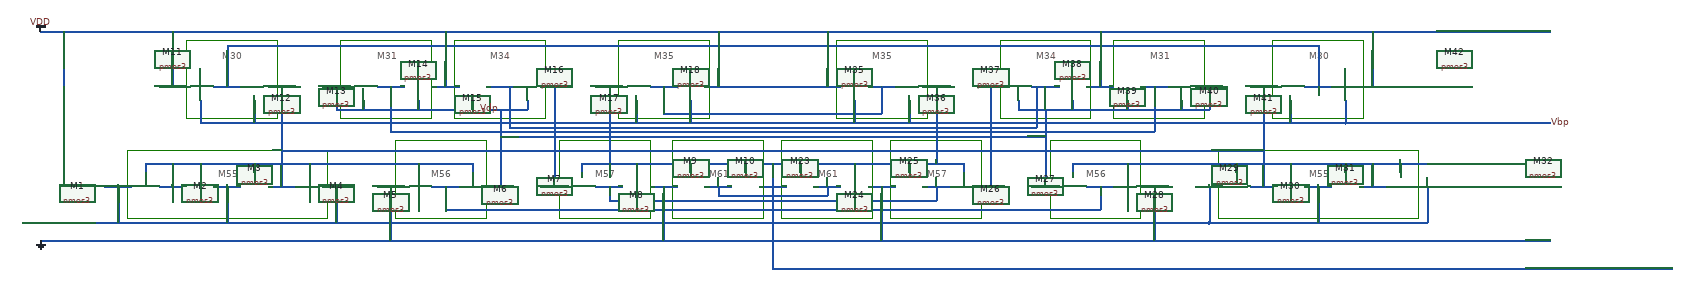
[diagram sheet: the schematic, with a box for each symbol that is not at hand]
v {xschem version=2.9.9 file_version=1.2 }
G {}
K {}
V {}
S {}
E {}
L 4 -700 -60 -500 -60 {}
L 4 -500 -230 -500 -60 {}
L 4 -700 -230 -500 -230 {}
L 4 -700 -230 -700 -60 {}
L 4 500 -60 700 -60 {}
L 4 700 -230 700 -60 {}
L 4 500 -230 700 -230 {}
L 4 500 -230 500 -60 {}
L 4 750 -60 950 -60 {}
L 4 950 -230 950 -60 {}
L 4 750 -230 950 -230 {}
L 4 750 -230 750 -60 {}
L 4 -950 -60 -750 -60 {}
L 4 -750 -230 -750 -60 {}
L 4 -950 -230 -750 -230 {}
L 4 -950 -230 -950 -60 {}
L 4 -1290 -60 -1090 -60 {}
L 4 -1090 -230 -1090 -60 {}
L 4 -1290 -230 -1090 -230 {}
L 4 -1290 -230 -1290 -60 {}
L 4 140 -60 340 -60 {}
L 4 340 -230 340 -60 {}
L 4 140 -230 340 -230 {}
L 4 140 -230 140 -60 {}
L 4 20 160 220 160 {}
L 4 220 -10 220 160 {}
L 4 20 -10 220 -10 {}
L 4 20 -10 20 160 {}
L 4 -220 160 -20 160 {}
L 4 -20 -10 -20 160 {}
L 4 -220 -10 -20 -10 {}
L 4 -220 -10 -220 160 {}
L 4 -470 160 -270 160 {}
L 4 -270 -10 -270 160 {}
L 4 -470 -10 -270 -10 {}
L 4 -470 -10 -470 160 {}
L 4 1100 -60 1300 -60 {}
L 4 1300 -230 1300 -60 {}
L 4 1100 -230 1300 -230 {}
L 4 1100 -230 1100 -60 {}
L 4 -1420 10 -1420 160 {}
L 4 -1420 160 -980 160 {}
L 4 -980 10 -980 160 {}
L 4 -1420 10 -980 10 {}
L 4 980 10 980 160 {}
L 4 980 160 1420 160 {}
L 4 1420 10 1420 160 {}
L 4 980 10 1420 10 {}
L 4 -830 160 -630 160 {}
L 4 -630 -10 -630 160 {}
L 4 -830 -10 -630 -10 {}
L 4 -830 -10 -830 160 {}
L 4 610 160 810 160 {}
L 4 810 -10 810 160 {}
L 4 610 -10 810 -10 {}
L 4 610 -10 610 160 {}
L 4 -340 -60 -140 -60 {}
L 4 -140 -230 -140 -60 {}
L 4 -340 -230 -140 -230 {}
L 4 -340 -230 -340 -60 {}
L 4 260 160 460 160 {}
L 4 460 -10 460 160 {}
L 4 260 -10 460 -10 {}
L 4 260 -10 260 160 {}
T {M34} -620 -210 0 0 0.4 0.4 {}
T {M34} 580 -210 0 0 0.4 0.4 {}
T {M31} 830 -210 0 0 0.4 0.4 {}
T {M31} -870 -210 0 0 0.4 0.4 {}
T {M30} -1210 -210 0 0 0.4 0.4 {}
T {M35} 220 -210 0 0 0.4 0.4 {}
T {M30} 1180 -210 0 0 0.4 0.4 {}
T {M55} -1220 50 0 0 0.4 0.4 {}
T {M55} 1180 50 0 0 0.4 0.4 {}
T {M56} -750 50 0 0 0.4 0.4 {}
T {M56} 690 50 0 0 0.4 0.4 {}
T {M35} -260 -210 0 0 0.4 0.4 {}
T {M57} 340 50 0 0 0.4 0.4 {}
T {M57} -390 50 0 0 0.4 0.4 {}
T {M61} -140 50 0 0 0.4 0.4 {}
T {M61} 100 50 0 0 0.4 0.4 {}
N -1020 40 -1020 60 { lab=#net1}
N -1140 40 -1140 60 { lab=#net1}
N -1260 40 -1260 60 { lab=#net1}
N -1380 40 -1380 60 { lab=#net1}
N -1350 90 -1290 90 { lab=#net1}
N -1230 90 -1170 90 { lab=#net2}
N -1110 90 -1050 90 { lab=#net1}
N -1230 -130 -1170 -130 { lab=#net3}
N -870 -130 -810 -130 { lab=#net4}
N -630 -130 -570 -130 { lab=#net5}
N -270 -130 -210 -130 { lab=#net6}
N -900 -100 -900 -80 { lab=Vdp}
N -540 -100 -540 -80 { lab=Vdp}
N -780 -100 -780 -80 { lab=Vdp}
N -660 -100 -660 -80 { lab=Vdp}
N -1260 -100 -1260 -50 { lab=Vbp}
N -180 -100 -180 -50 { lab=Vbp}
N -300 -100 -300 -50 { lab=Vbp}
N -1140 -100 -1140 -50 { lab=Vbp}
N -1320 -250 -1320 -130 { lab=VDD}
N -120 -250 -120 -130 { lab=VDD}
N -750 -130 -690 -130 { lab=VDD}
N -720 -250 -720 -130 { lab=VDD}
N -780 40 -780 60 { lab=#net1}
N -660 40 -660 60 { lab=#net1}
N -750 90 -690 90 { lab=#net7}
N -390 90 -330 90 { lab=#net8}
N -150 90 -90 90 { lab=#net9}
N -960 90 -960 170 { lab=#net2}
N -420 40 -420 60 { lab=#net10}
N -60 40 -60 60 { lab=#net10}
N -180 40 -180 60 { lab=#net10}
N -300 40 -300 60 { lab=#net10}
N -270 90 -210 90 { lab=GND}
N -240 90 -240 210 { lab=GND}
N -840 90 -840 210 { lab=GND}
N 0 40 0 90 { lab=#net10}
N -480 -50 -480 90 { lab=Vbp}
N -1110 -130 -1050 -130 { lab=#net1}
N -990 -130 -930 -130 { lab=Vdp}
N -1080 -130 -1080 40 { lab=#net1}
N -390 -130 -330 -130 { lab=#net10}
N -360 -130 -360 40 { lab=#net10}
N -510 -130 -450 -130 { lab=Vbp}
N -480 -130 -480 -50 { lab=Vbp}
N -870 90 -810 90 { lab=GND}
N -990 90 -930 90 { lab=#net2}
N -630 90 -570 90 { lab=Vdp}
N -600 -80 -600 90 { lab=Vdp}
N -510 90 -450 90 { lab=Vbp}
N 60 40 60 60 { lab=#net10}
N 180 40 180 60 { lab=#net10}
N 300 40 300 60 { lab=#net10}
N 420 40 420 60 { lab=#net10}
N -30 90 30 90 { lab=#net10}
N -420 40 420 40 { lab=#net10}
N 90 90 150 90 { lab=#net9}
N 210 90 270 90 { lab=GND}
N 330 90 390 90 { lab=#net8}
N 240 90 240 210 { lab=GND}
N -150 -130 -90 -130 { lab=VDD}
N 90 -130 150 -130 { lab=VDD}
N 120 -250 120 -130 { lab=VDD}
N 180 -100 180 -50 { lab=Vbp}
N 300 -100 300 -50 { lab=Vbp}
N 1260 -100 1260 -50 { lab=Vbp}
N 1140 -100 1140 -50 { lab=Vbp}
N 540 -100 540 -80 { lab=Vdp}
N 660 -100 660 -80 { lab=Vdp}
N 780 -100 780 -80 { lab=Vdp}
N 900 -100 900 -80 { lab=Vdp}
N -960 -130 -960 -80 { lab=Vdp}
N -960 -80 -540 -80 { lab=Vdp}
N 210 -130 270 -130 { lab=#net6}
N 330 -130 390 -130 { lab=#net10}
N 450 -130 510 -130 { lab=Vbp}
N 570 -130 630 -130 { lab=#net5}
N 690 -130 750 -130 { lab=VDD}
N 810 -130 870 -130 { lab=#net4}
N 930 -130 990 -130 { lab=Vdp}
N 1050 -130 1110 -130 { lab=#net1}
N 1170 -130 1230 -130 { lab=#net3}
N 450 90 510 90 { lab=Vbp}
N 570 90 630 90 { lab=Vdp}
N 690 90 750 90 { lab=#net7}
N 810 90 870 90 { lab=GND}
N 930 90 990 90 { lab=#net2}
N 1050 90 1110 90 { lab=#net1}
N 1170 90 1230 90 { lab=#net2}
N 1290 90 1350 90 { lab=#net1}
N 1380 40 1380 60 { lab=#net1}
N 1020 40 1020 60 { lab=#net1}
N 1140 40 1140 60 { lab=#net1}
N 1260 40 1260 60 { lab=#net1}
N -1260 -50 1260 -50 { lab=Vbp}
N 960 -130 960 -80 { lab=Vdp}
N 540 -80 960 -80 { lab=Vdp}
N 360 -130 360 40 { lab=#net10}
N 480 -130 480 -50 { lab=Vbp}
N 480 -50 480 90 { lab=Vbp}
N 840 90 840 210 { lab=GND}
N 960 90 960 170 { lab=#net2}
N 600 -80 600 90 { lab=Vdp}
N 660 40 660 60 { lab=#net1}
N 780 40 780 60 { lab=#net1}
N 660 40 1440 40 { lab=#net1}
N 1320 -250 1320 -130 { lab=VDD}
N 1080 -130 1080 40 { lab=#net1}
N -600 -20 600 -20 { lab=Vdp}
N -1080 10 1080 10 { lab=#net1}
N 0 90 0 270 { lab=#net10}
N -1350 -130 -1290 -130 { lab=VDD}
N -1470 90 -1410 90 { lab=#net2}
N 1410 90 1470 90 { lab=#net2}
N 1290 -130 1350 -130 { lab=VDD}
N -1610 170 960 170 { lab=#net2}
N -1610 210 1710 210 { lab=GND}
N 0 270 1710 270 { lab=#net10}
N 1260 -50 1710 -50 { lab=Vbp}
N -1610 -250 1710 -250 { lab=VDD}
N -1560 -250 -1560 -130 { lab=VDD}
N -1200 90 -1200 160 { lab=#net2}
N -1200 160 -1200 170 { lab=#net2}
N -1080 40 -1080 90 { lab=#net1}
N -1320 40 -1320 90 { lab=#net1}
N -1440 90 -1440 170 { lab=#net2}
N -1380 40 -660 40 { lab=#net1}
N 960 170 1440 170 { lab=#net2}
N 1440 90 1440 170 { lab=#net2}
N 1200 90 1200 170 { lab=#net2}
N 1080 40 1080 90 { lab=#net1}
N 1320 40 1320 90 { lab=#net1}
N 1710 270 1980 270 { lab=#net10}
N -1650 170 -1610 170 { lab=#net2}
N -840 -130 -840 -30 { lab=#net4}
N -840 -30 840 -30 { lab=#net4}
N 840 -130 840 -30 { lab=#net4}
N -580 -130 -580 -40 { lab=#net5}
N -580 -40 580 -40 { lab=#net5}
N 580 -130 580 -40 { lab=#net5}
N -240 -130 -240 -70 { lab=#net6}
N -240 -70 240 -70 { lab=#net6}
N 240 -130 240 -70 { lab=#net6}
N -1200 -220 -1200 -130 { lab=#net3}
N -1200 -220 1200 -220 { lab=#net3}
N 1200 -220 1200 -130 { lab=#net3}
N -720 90 -720 140 { lab=#net7}
N -720 140 720 140 { lab=#net7}
N 720 90 720 140 { lab=#net7}
N 360 90 360 120 { lab=#net8}
N -350 120 360 120 { lab=#net8}
N -360 120 -350 120 { lab=#net8}
N -360 90 -360 120 { lab=#net8}
N -120 90 -120 110 { lab=#net9}
N -120 110 120 110 { lab=#net9}
N 120 90 120 110 { lab=#net9}
N 720 -250 720 -130 { lab=VDD}
N -90 -130 90 -130 { lab=VDD}
C {madvlsi/nmos3.sym} -1380 90 1 0 {name=M1
L=4.0
W=16
body=GND
nf=1
mult=1
ad="'int((nf+1)/2) * W/nf * 0.29'" 
pd="'2*int((nf+1)/2) * (W/nf + 0.29)'"
as="'int((nf+2)/2) * W/nf * 0.29'" 
ps="'2*int((nf+2)/2) * (W/nf + 0.29)'"
nrd="'0.29 / W'" nrs="'0.29 / W'"
sa=0 sb=0 sd=0
model=nfet_01v8
spiceprefix=X
}
C {madvlsi/nmos3.sym} -1260 90 1 0 {name=M2
L=4.0
W=16
body=GND
nf=1
mult=1
ad="'int((nf+1)/2) * W/nf * 0.29'" 
pd="'2*int((nf+1)/2) * (W/nf + 0.29)'"
as="'int((nf+2)/2) * W/nf * 0.29'" 
ps="'2*int((nf+2)/2) * (W/nf + 0.29)'"
nrd="'0.29 / W'" nrs="'0.29 / W'"
sa=0 sb=0 sd=0
model=nfet_01v8
spiceprefix=X
}
C {madvlsi/nmos3.sym} -1140 90 1 0 {name=M3
L=4.0
W=16
body=GND
nf=1
mult=1
ad="'int((nf+1)/2) * W/nf * 0.29'" 
pd="'2*int((nf+1)/2) * (W/nf + 0.29)'"
as="'int((nf+2)/2) * W/nf * 0.29'" 
ps="'2*int((nf+2)/2) * (W/nf + 0.29)'"
nrd="'0.29 / W'" nrs="'0.29 / W'"
sa=0 sb=0 sd=0
model=nfet_01v8
spiceprefix=X
}
C {madvlsi/nmos3.sym} -1020 90 1 0 {name=M4
L=4.0
W=16
body=GND
nf=1
mult=1
ad="'int((nf+1)/2) * W/nf * 0.29'" 
pd="'2*int((nf+1)/2) * (W/nf + 0.29)'"
as="'int((nf+2)/2) * W/nf * 0.29'" 
ps="'2*int((nf+2)/2) * (W/nf + 0.29)'"
nrd="'0.29 / W'" nrs="'0.29 / W'"
sa=0 sb=0 sd=0
model=nfet_01v8
spiceprefix=X
}
C {madvlsi/nmos3.sym} -780 90 1 0 {name=M5
L=4.0
W=16
body=GND
nf=1
mult=1
ad="'int((nf+1)/2) * W/nf * 0.29'" 
pd="'2*int((nf+1)/2) * (W/nf + 0.29)'"
as="'int((nf+2)/2) * W/nf * 0.29'" 
ps="'2*int((nf+2)/2) * (W/nf + 0.29)'"
nrd="'0.29 / W'" nrs="'0.29 / W'"
sa=0 sb=0 sd=0
model=nfet_01v8
spiceprefix=X
}
C {madvlsi/nmos3.sym} -660 90 1 0 {name=M6
L=4.0
W=16
body=GND
nf=1
mult=1
ad="'int((nf+1)/2) * W/nf * 0.29'" 
pd="'2*int((nf+1)/2) * (W/nf + 0.29)'"
as="'int((nf+2)/2) * W/nf * 0.29'" 
ps="'2*int((nf+2)/2) * (W/nf + 0.29)'"
nrd="'0.29 / W'" nrs="'0.29 / W'"
sa=0 sb=0 sd=0
model=nfet_01v8
spiceprefix=X
}
C {madvlsi/nmos3.sym} -420 90 1 0 {name=M7
L=4.0
W=16
body=GND
nf=1
mult=1
ad="'int((nf+1)/2) * W/nf * 0.29'" 
pd="'2*int((nf+1)/2) * (W/nf + 0.29)'"
as="'int((nf+2)/2) * W/nf * 0.29'" 
ps="'2*int((nf+2)/2) * (W/nf + 0.29)'"
nrd="'0.29 / W'" nrs="'0.29 / W'"
sa=0 sb=0 sd=0
model=nfet_01v8
spiceprefix=X
}
C {madvlsi/nmos3.sym} -300 90 1 0 {name=M8
L=4.0
W=16
body=GND
nf=1
mult=1
ad="'int((nf+1)/2) * W/nf * 0.29'" 
pd="'2*int((nf+1)/2) * (W/nf + 0.29)'"
as="'int((nf+2)/2) * W/nf * 0.29'" 
ps="'2*int((nf+2)/2) * (W/nf + 0.29)'"
nrd="'0.29 / W'" nrs="'0.29 / W'"
sa=0 sb=0 sd=0
model=nfet_01v8
spiceprefix=X
}
C {madvlsi/nmos3.sym} -180 90 1 0 {name=M9
L=4.0
W=16
body=GND
nf=1
mult=1
ad="'int((nf+1)/2) * W/nf * 0.29'" 
pd="'2*int((nf+1)/2) * (W/nf + 0.29)'"
as="'int((nf+2)/2) * W/nf * 0.29'" 
ps="'2*int((nf+2)/2) * (W/nf + 0.29)'"
nrd="'0.29 / W'" nrs="'0.29 / W'"
sa=0 sb=0 sd=0
model=nfet_01v8
spiceprefix=X
}
C {madvlsi/nmos3.sym} -60 90 1 0 {name=M10
L=4.0
W=16
body=GND
nf=1
mult=1
ad="'int((nf+1)/2) * W/nf * 0.29'" 
pd="'2*int((nf+1)/2) * (W/nf + 0.29)'"
as="'int((nf+2)/2) * W/nf * 0.29'" 
ps="'2*int((nf+2)/2) * (W/nf + 0.29)'"
nrd="'0.29 / W'" nrs="'0.29 / W'"
sa=0 sb=0 sd=0
model=nfet_01v8
spiceprefix=X
}
C {madvlsi/pmos3.sym} -1260 -130 1 1 {name=M11
L=4.0
W=16
body=VDD
nf=1
mult=1
ad="'int((nf+1)/2) * W/nf * 0.29'" 
pd="'2*int((nf+1)/2) * (W/nf + 0.29)'"
as="'int((nf+2)/2) * W/nf * 0.29'" 
ps="'2*int((nf+2)/2) * (W/nf + 0.29)'"
nrd="'0.29 / W'" nrs="'0.29 / W'"
sa=0 sb=0 sd=0
model=pfet_01v8
spiceprefix=X
}
C {madvlsi/pmos3.sym} -1140 -130 1 1 {name=M12
L=4.0
W=16
body=VDD
nf=1
mult=1
ad="'int((nf+1)/2) * W/nf * 0.29'" 
pd="'2*int((nf+1)/2) * (W/nf + 0.29)'"
as="'int((nf+2)/2) * W/nf * 0.29'" 
ps="'2*int((nf+2)/2) * (W/nf + 0.29)'"
nrd="'0.29 / W'" nrs="'0.29 / W'"
sa=0 sb=0 sd=0
model=pfet_01v8
spiceprefix=X
}
C {madvlsi/pmos3.sym} -900 -130 1 1 {name=M13
L=4.0
W=16
body=VDD
nf=1
mult=1
ad="'int((nf+1)/2) * W/nf * 0.29'" 
pd="'2*int((nf+1)/2) * (W/nf + 0.29)'"
as="'int((nf+2)/2) * W/nf * 0.29'" 
ps="'2*int((nf+2)/2) * (W/nf + 0.29)'"
nrd="'0.29 / W'" nrs="'0.29 / W'"
sa=0 sb=0 sd=0
model=pfet_01v8
spiceprefix=X
}
C {madvlsi/pmos3.sym} -780 -130 1 1 {name=M14
L=4.0
W=16
body=VDD
nf=1
mult=1
ad="'int((nf+1)/2) * W/nf * 0.29'" 
pd="'2*int((nf+1)/2) * (W/nf + 0.29)'"
as="'int((nf+2)/2) * W/nf * 0.29'" 
ps="'2*int((nf+2)/2) * (W/nf + 0.29)'"
nrd="'0.29 / W'" nrs="'0.29 / W'"
sa=0 sb=0 sd=0
model=pfet_01v8
spiceprefix=X
}
C {madvlsi/pmos3.sym} -660 -130 1 1 {name=M15
L=4.0
W=16
body=VDD
nf=1
mult=1
ad="'int((nf+1)/2) * W/nf * 0.29'" 
pd="'2*int((nf+1)/2) * (W/nf + 0.29)'"
as="'int((nf+2)/2) * W/nf * 0.29'" 
ps="'2*int((nf+2)/2) * (W/nf + 0.29)'"
nrd="'0.29 / W'" nrs="'0.29 / W'"
sa=0 sb=0 sd=0
model=pfet_01v8
spiceprefix=X
}
C {madvlsi/pmos3.sym} -540 -130 1 1 {name=M16
L=4.0
W=16
body=VDD
nf=1
mult=1
ad="'int((nf+1)/2) * W/nf * 0.29'" 
pd="'2*int((nf+1)/2) * (W/nf + 0.29)'"
as="'int((nf+2)/2) * W/nf * 0.29'" 
ps="'2*int((nf+2)/2) * (W/nf + 0.29)'"
nrd="'0.29 / W'" nrs="'0.29 / W'"
sa=0 sb=0 sd=0
model=pfet_01v8
spiceprefix=X
}
C {madvlsi/pmos3.sym} -300 -130 1 1 {name=M17
L=4.0
W=16
body=VDD
nf=1
mult=1
ad="'int((nf+1)/2) * W/nf * 0.29'" 
pd="'2*int((nf+1)/2) * (W/nf + 0.29)'"
as="'int((nf+2)/2) * W/nf * 0.29'" 
ps="'2*int((nf+2)/2) * (W/nf + 0.29)'"
nrd="'0.29 / W'" nrs="'0.29 / W'"
sa=0 sb=0 sd=0
model=pfet_01v8
spiceprefix=X
}
C {madvlsi/pmos3.sym} -180 -130 1 1 {name=M18
L=4.0
W=16
body=VDD
nf=1
mult=1
ad="'int((nf+1)/2) * W/nf * 0.29'" 
pd="'2*int((nf+1)/2) * (W/nf + 0.29)'"
as="'int((nf+2)/2) * W/nf * 0.29'" 
ps="'2*int((nf+2)/2) * (W/nf + 0.29)'"
nrd="'0.29 / W'" nrs="'0.29 / W'"
sa=0 sb=0 sd=0
model=pfet_01v8
spiceprefix=X
}
C {madvlsi/nmos3.sym} 60 90 1 0 {name=M23
L=4.0
W=16
body=GND
nf=1
mult=1
ad="'int((nf+1)/2) * W/nf * 0.29'" 
pd="'2*int((nf+1)/2) * (W/nf + 0.29)'"
as="'int((nf+2)/2) * W/nf * 0.29'" 
ps="'2*int((nf+2)/2) * (W/nf + 0.29)'"
nrd="'0.29 / W'" nrs="'0.29 / W'"
sa=0 sb=0 sd=0
model=nfet_01v8
spiceprefix=X
}
C {madvlsi/nmos3.sym} 180 90 1 0 {name=M24
L=4.0
W=16
body=GND
nf=1
mult=1
ad="'int((nf+1)/2) * W/nf * 0.29'" 
pd="'2*int((nf+1)/2) * (W/nf + 0.29)'"
as="'int((nf+2)/2) * W/nf * 0.29'" 
ps="'2*int((nf+2)/2) * (W/nf + 0.29)'"
nrd="'0.29 / W'" nrs="'0.29 / W'"
sa=0 sb=0 sd=0
model=nfet_01v8
spiceprefix=X
}
C {madvlsi/nmos3.sym} 300 90 1 0 {name=M25
L=4.0
W=16
body=GND
nf=1
mult=1
ad="'int((nf+1)/2) * W/nf * 0.29'" 
pd="'2*int((nf+1)/2) * (W/nf + 0.29)'"
as="'int((nf+2)/2) * W/nf * 0.29'" 
ps="'2*int((nf+2)/2) * (W/nf + 0.29)'"
nrd="'0.29 / W'" nrs="'0.29 / W'"
sa=0 sb=0 sd=0
model=nfet_01v8
spiceprefix=X
}
C {madvlsi/nmos3.sym} 420 90 1 0 {name=M26
L=4.0
W=16
body=GND
nf=1
mult=1
ad="'int((nf+1)/2) * W/nf * 0.29'" 
pd="'2*int((nf+1)/2) * (W/nf + 0.29)'"
as="'int((nf+2)/2) * W/nf * 0.29'" 
ps="'2*int((nf+2)/2) * (W/nf + 0.29)'"
nrd="'0.29 / W'" nrs="'0.29 / W'"
sa=0 sb=0 sd=0
model=nfet_01v8
spiceprefix=X
}
C {madvlsi/nmos3.sym} 660 90 1 0 {name=M27
L=4.0
W=16
body=GND
nf=1
mult=1
ad="'int((nf+1)/2) * W/nf * 0.29'" 
pd="'2*int((nf+1)/2) * (W/nf + 0.29)'"
as="'int((nf+2)/2) * W/nf * 0.29'" 
ps="'2*int((nf+2)/2) * (W/nf + 0.29)'"
nrd="'0.29 / W'" nrs="'0.29 / W'"
sa=0 sb=0 sd=0
model=nfet_01v8
spiceprefix=X
}
C {madvlsi/nmos3.sym} 780 90 1 0 {name=M28
L=4.0
W=16
body=GND
nf=1
mult=1
ad="'int((nf+1)/2) * W/nf * 0.29'" 
pd="'2*int((nf+1)/2) * (W/nf + 0.29)'"
as="'int((nf+2)/2) * W/nf * 0.29'" 
ps="'2*int((nf+2)/2) * (W/nf + 0.29)'"
nrd="'0.29 / W'" nrs="'0.29 / W'"
sa=0 sb=0 sd=0
model=nfet_01v8
spiceprefix=X
}
C {madvlsi/nmos3.sym} 1020 90 1 0 {name=M29
L=4.0
W=16
body=GND
nf=1
mult=1
ad="'int((nf+1)/2) * W/nf * 0.29'" 
pd="'2*int((nf+1)/2) * (W/nf + 0.29)'"
as="'int((nf+2)/2) * W/nf * 0.29'" 
ps="'2*int((nf+2)/2) * (W/nf + 0.29)'"
nrd="'0.29 / W'" nrs="'0.29 / W'"
sa=0 sb=0 sd=0
model=nfet_01v8
spiceprefix=X
}
C {madvlsi/nmos3.sym} 1140 90 1 0 {name=M30
L=4.0
W=16
body=GND
nf=1
mult=1
ad="'int((nf+1)/2) * W/nf * 0.29'" 
pd="'2*int((nf+1)/2) * (W/nf + 0.29)'"
as="'int((nf+2)/2) * W/nf * 0.29'" 
ps="'2*int((nf+2)/2) * (W/nf + 0.29)'"
nrd="'0.29 / W'" nrs="'0.29 / W'"
sa=0 sb=0 sd=0
model=nfet_01v8
spiceprefix=X
}
C {madvlsi/nmos3.sym} 1260 90 1 0 {name=M31
L=4.0
W=16
body=GND
nf=1
mult=1
ad="'int((nf+1)/2) * W/nf * 0.29'" 
pd="'2*int((nf+1)/2) * (W/nf + 0.29)'"
as="'int((nf+2)/2) * W/nf * 0.29'" 
ps="'2*int((nf+2)/2) * (W/nf + 0.29)'"
nrd="'0.29 / W'" nrs="'0.29 / W'"
sa=0 sb=0 sd=0
model=nfet_01v8
spiceprefix=X
}
C {madvlsi/nmos3.sym} 1380 90 1 0 {name=M32
L=4.0
W=16
body=GND
nf=1
mult=1
ad="'int((nf+1)/2) * W/nf * 0.29'" 
pd="'2*int((nf+1)/2) * (W/nf + 0.29)'"
as="'int((nf+2)/2) * W/nf * 0.29'" 
ps="'2*int((nf+2)/2) * (W/nf + 0.29)'"
nrd="'0.29 / W'" nrs="'0.29 / W'"
sa=0 sb=0 sd=0
model=nfet_01v8
spiceprefix=X
}
C {madvlsi/pmos3.sym} 180 -130 1 1 {name=M35
L=4.0
W=16
body=VDD
nf=1
mult=1
ad="'int((nf+1)/2) * W/nf * 0.29'" 
pd="'2*int((nf+1)/2) * (W/nf + 0.29)'"
as="'int((nf+2)/2) * W/nf * 0.29'" 
ps="'2*int((nf+2)/2) * (W/nf + 0.29)'"
nrd="'0.29 / W'" nrs="'0.29 / W'"
sa=0 sb=0 sd=0
model=pfet_01v8
spiceprefix=X
}
C {madvlsi/pmos3.sym} 300 -130 1 1 {name=M36
L=4.0
W=16
body=VDD
nf=1
mult=1
ad="'int((nf+1)/2) * W/nf * 0.29'" 
pd="'2*int((nf+1)/2) * (W/nf + 0.29)'"
as="'int((nf+2)/2) * W/nf * 0.29'" 
ps="'2*int((nf+2)/2) * (W/nf + 0.29)'"
nrd="'0.29 / W'" nrs="'0.29 / W'"
sa=0 sb=0 sd=0
model=pfet_01v8
spiceprefix=X
}
C {madvlsi/pmos3.sym} 540 -130 1 1 {name=M37
L=4.0
W=16
body=VDD
nf=1
mult=1
ad="'int((nf+1)/2) * W/nf * 0.29'" 
pd="'2*int((nf+1)/2) * (W/nf + 0.29)'"
as="'int((nf+2)/2) * W/nf * 0.29'" 
ps="'2*int((nf+2)/2) * (W/nf + 0.29)'"
nrd="'0.29 / W'" nrs="'0.29 / W'"
sa=0 sb=0 sd=0
model=pfet_01v8
spiceprefix=X
}
C {madvlsi/pmos3.sym} 660 -130 1 1 {name=M38
L=4.0
W=16
body=VDD
nf=1
mult=1
ad="'int((nf+1)/2) * W/nf * 0.29'" 
pd="'2*int((nf+1)/2) * (W/nf + 0.29)'"
as="'int((nf+2)/2) * W/nf * 0.29'" 
ps="'2*int((nf+2)/2) * (W/nf + 0.29)'"
nrd="'0.29 / W'" nrs="'0.29 / W'"
sa=0 sb=0 sd=0
model=pfet_01v8
spiceprefix=X
}
C {madvlsi/pmos3.sym} 780 -130 1 1 {name=M39
L=4.0
W=16
body=VDD
nf=1
mult=1
ad="'int((nf+1)/2) * W/nf * 0.29'" 
pd="'2*int((nf+1)/2) * (W/nf + 0.29)'"
as="'int((nf+2)/2) * W/nf * 0.29'" 
ps="'2*int((nf+2)/2) * (W/nf + 0.29)'"
nrd="'0.29 / W'" nrs="'0.29 / W'"
sa=0 sb=0 sd=0
model=pfet_01v8
spiceprefix=X
}
C {madvlsi/pmos3.sym} 900 -130 1 1 {name=M40
L=4.0
W=16
body=VDD
nf=1
mult=1
ad="'int((nf+1)/2) * W/nf * 0.29'" 
pd="'2*int((nf+1)/2) * (W/nf + 0.29)'"
as="'int((nf+2)/2) * W/nf * 0.29'" 
ps="'2*int((nf+2)/2) * (W/nf + 0.29)'"
nrd="'0.29 / W'" nrs="'0.29 / W'"
sa=0 sb=0 sd=0
model=pfet_01v8
spiceprefix=X
}
C {madvlsi/pmos3.sym} 1140 -130 1 1 {name=M41
L=4.0
W=16
body=VDD
nf=1
mult=1
ad="'int((nf+1)/2) * W/nf * 0.29'" 
pd="'2*int((nf+1)/2) * (W/nf + 0.29)'"
as="'int((nf+2)/2) * W/nf * 0.29'" 
ps="'2*int((nf+2)/2) * (W/nf + 0.29)'"
nrd="'0.29 / W'" nrs="'0.29 / W'"
sa=0 sb=0 sd=0
model=pfet_01v8
spiceprefix=X
}
C {madvlsi/pmos3.sym} 1260 -130 1 1 {name=M42
L=4.0
W=16
body=VDD
nf=1
mult=1
ad="'int((nf+1)/2) * W/nf * 0.29'" 
pd="'2*int((nf+1)/2) * (W/nf + 0.29)'"
as="'int((nf+2)/2) * W/nf * 0.29'" 
ps="'2*int((nf+2)/2) * (W/nf + 0.29)'"
nrd="'0.29 / W'" nrs="'0.29 / W'"
sa=0 sb=0 sd=0
model=pfet_01v8
spiceprefix=X
}
C {madvlsi/gnd.sym} -1610 210 1 0 {name=l5 lab=GND}
C {madvlsi/vdd.sym} -1610 -250 3 0 {name=l9 lab=VDD}
C {devices/lab_pin.sym} -600 -80 1 0 {name=l4 sig_type=std_logic lab=Vdp}
C {devices/lab_pin.sym} 1710 -50 2 0 {name=l30 sig_type=std_logic lab=Vbp}
